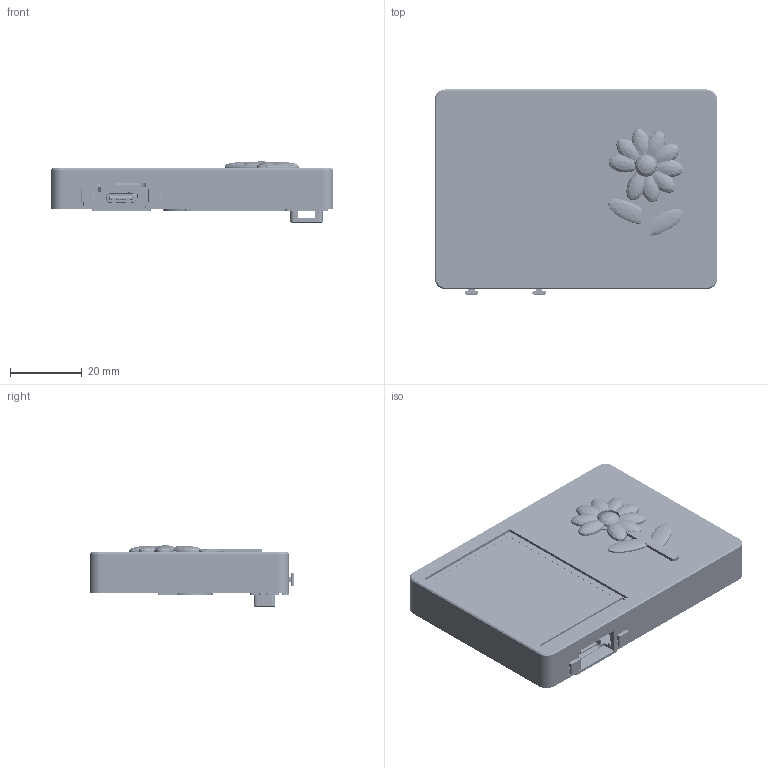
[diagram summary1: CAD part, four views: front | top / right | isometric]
STEP (ISO 10303-21) file: header records copied from the file, then geometry measured from it (millimetres).
FILE_DESCRIPTION(('Open CASCADE Model'),'2;1');
FILE_NAME('Open CASCADE Shape Model','2026-11-25T12:45:01',('Author'),( 'Open CASCADE'),'Open CASCADE STEP processor 7.9','Open CASCADE 7.9' ,'Unknown');
FILE_SCHEMA(('AUTOMOTIVE_DESIGN { 1 0 10303 214 1 1 1 1 }'));
Length unit declared in the file: millimetre
Products named in the file (11): NianNian_V12_11p4mm; A_main_two_bay; C_rear_cover; E_battery_spacer; K_BOOT_cap; K_RST_cap; hardware; battery; D_daisy_petals; D2_daisy_center; D3_stem_leaves
Assembly tree (10 placements, depth 2):
  NianNian_V12_11p4mm
    A_main_two_bay
    C_rear_cover
    E_battery_spacer
    K_BOOT_cap
    K_RST_cap
    hardware
    battery
    D_daisy_petals
    D2_daisy_center
    D3_stem_leaves
Bounding box: 79 x 57.3 x 17.2 mm (x, y, z)
Volume: 34876.8 mm3; surface area: 47404.6 mm2
Topology: 333 solids, 345 shells, 18054 faces, 47680 edges, 30993 vertices
Faces by surface type: plane 11942, extrusion 3289, cylinder 2337, sphere 331, cone 65, bspline 46, torus 44
Full cylindrical faces by diameter (mm): 1.1 x2, 1.2 x2, 1.4 x2, 1.9 x2, 3 x5, 6.57 x2
Entity records: 1404086 total; most frequent: CARTESIAN_POINT 481151, DIRECTION 155706, VECTOR 114755, LINE 111466, ORIENTED_EDGE 94686, PCURVE 94686, DEFINITIONAL_REPRESENTATION 94686, EDGE_CURVE 47343
One B-rep face of a CAD part: STEP entity #33258.
In plain terms, the planar face has unit normal (0, 0, 1).
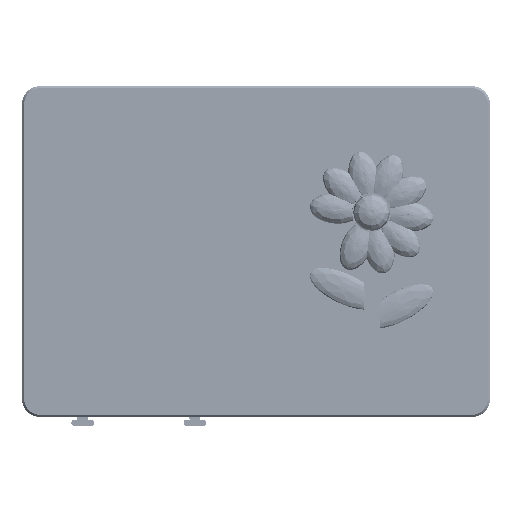
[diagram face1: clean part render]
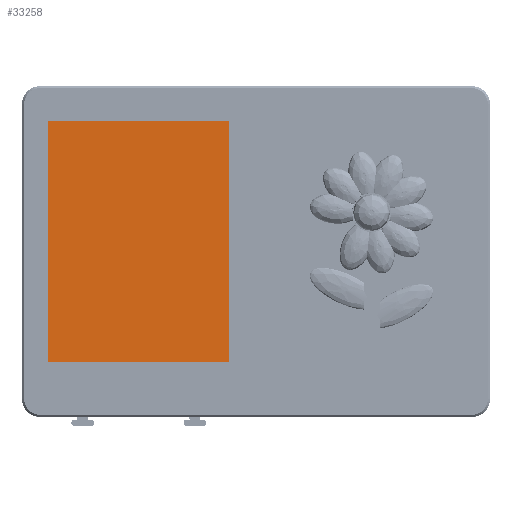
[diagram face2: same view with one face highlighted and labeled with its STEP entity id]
Its self-contained STEP definition (entity closure, numbers rounded to 3 decimals):
#33089 = PLANE('',#33090);
#33090 = AXIS2_PLACEMENT_3D('',#33091,#33092,#33093);
#33091 = CARTESIAN_POINT('',(-35.1,22.1,10.3));
#33092 = DIRECTION('',(0.,-1.,0.));
#33093 = DIRECTION('',(1.,0.,0.));
#33117 = PLANE('',#33118);
#33118 = AXIS2_PLACEMENT_3D('',#33119,#33120,#33121);
#33119 = CARTESIAN_POINT('',(-35.1,-18.7,10.3));
#33120 = DIRECTION('',(1.,0.,0.));
#33121 = DIRECTION('',(0.,1.,0.));
#33145 = PLANE('',#33146);
#33146 = AXIS2_PLACEMENT_3D('',#33147,#33148,#33149);
#33147 = CARTESIAN_POINT('',(-4.5,-18.7,10.3));
#33148 = DIRECTION('',(0.,1.,0.));
#33149 = DIRECTION('',(-1.,0.,0.));
#33171 = PLANE('',#33172);
#33172 = AXIS2_PLACEMENT_3D('',#33173,#33174,#33175);
#33173 = CARTESIAN_POINT('',(-4.5,22.1,10.3));
#33174 = DIRECTION('',(-1.,0.,0.));
#33175 = DIRECTION('',(0.,-1.,0.));
#33186 = EDGE_CURVE('',#33187,#33189,#33191,.T.);
#33187 = VERTEX_POINT('',#33188);
#33188 = CARTESIAN_POINT('',(-35.1,22.1,10.35));
#33189 = VERTEX_POINT('',#33190);
#33190 = CARTESIAN_POINT('',(-4.5,22.1,10.35));
#33191 = SURFACE_CURVE('',#33192,(#33196,#33203),.PCURVE_S1.);
#33192 = LINE('',#33193,#33194);
#33193 = CARTESIAN_POINT('',(-35.1,22.1,10.35));
#33194 = VECTOR('',#33195,1.);
#33195 = DIRECTION('',(1.,0.,0.));
#33196 = PCURVE('',#33089,#33197);
#33197 = DEFINITIONAL_REPRESENTATION('',(#33198),#33202);
#33198 = LINE('',#33199,#33200);
#33199 = CARTESIAN_POINT('',(0.,0.05));
#33200 = VECTOR('',#33201,1.);
#33201 = DIRECTION('',(1.,0.));
#33202 = ( GEOMETRIC_REPRESENTATION_CONTEXT(2) 
PARAMETRIC_REPRESENTATION_CONTEXT() REPRESENTATION_CONTEXT('2D SPACE',''
  ) );
#33203 = PCURVE('',#33204,#33209);
#33204 = PLANE('',#33205);
#33205 = AXIS2_PLACEMENT_3D('',#33206,#33207,#33208);
#33206 = CARTESIAN_POINT('',(-19.8,1.7,10.35));
#33207 = DIRECTION('',(0.,0.,1.));
#33208 = DIRECTION('',(1.,0.,0.));
#33209 = DEFINITIONAL_REPRESENTATION('',(#33210),#33214);
#33210 = LINE('',#33211,#33212);
#33211 = CARTESIAN_POINT('',(-15.3,20.4));
#33212 = VECTOR('',#33213,1.);
#33213 = DIRECTION('',(1.,0.));
#33214 = ( GEOMETRIC_REPRESENTATION_CONTEXT(2) 
PARAMETRIC_REPRESENTATION_CONTEXT() REPRESENTATION_CONTEXT('2D SPACE',''
  ) );
#33258 = ADVANCED_FACE('',(#33259),#33204,.T.);
#33259 = FACE_BOUND('',#33260,.F.);
#33260 = EDGE_LOOP('',(#33261,#33262,#33285,#33308));
#33261 = ORIENTED_EDGE('',*,*,#33186,.T.);
#33262 = ORIENTED_EDGE('',*,*,#33263,.F.);
#33263 = EDGE_CURVE('',#33264,#33189,#33266,.T.);
#33264 = VERTEX_POINT('',#33265);
#33265 = CARTESIAN_POINT('',(-4.5,-18.7,10.35));
#33266 = SURFACE_CURVE('',#33267,(#33271,#33278),.PCURVE_S1.);
#33267 = LINE('',#33268,#33269);
#33268 = CARTESIAN_POINT('',(-4.5,-18.7,10.35));
#33269 = VECTOR('',#33270,1.);
#33270 = DIRECTION('',(0.,1.,0.));
#33271 = PCURVE('',#33204,#33272);
#33272 = DEFINITIONAL_REPRESENTATION('',(#33273),#33277);
#33273 = LINE('',#33274,#33275);
#33274 = CARTESIAN_POINT('',(15.3,-20.4));
#33275 = VECTOR('',#33276,1.);
#33276 = DIRECTION('',(0.,1.));
#33277 = ( GEOMETRIC_REPRESENTATION_CONTEXT(2) 
PARAMETRIC_REPRESENTATION_CONTEXT() REPRESENTATION_CONTEXT('2D SPACE',''
  ) );
#33278 = PCURVE('',#33171,#33279);
#33279 = DEFINITIONAL_REPRESENTATION('',(#33280),#33284);
#33280 = LINE('',#33281,#33282);
#33281 = CARTESIAN_POINT('',(40.8,0.05));
#33282 = VECTOR('',#33283,1.);
#33283 = DIRECTION('',(-1.,0.));
#33284 = ( GEOMETRIC_REPRESENTATION_CONTEXT(2) 
PARAMETRIC_REPRESENTATION_CONTEXT() REPRESENTATION_CONTEXT('2D SPACE',''
  ) );
#33285 = ORIENTED_EDGE('',*,*,#33286,.F.);
#33286 = EDGE_CURVE('',#33287,#33264,#33289,.T.);
#33287 = VERTEX_POINT('',#33288);
#33288 = CARTESIAN_POINT('',(-35.1,-18.7,10.35));
#33289 = SURFACE_CURVE('',#33290,(#33294,#33301),.PCURVE_S1.);
#33290 = LINE('',#33291,#33292);
#33291 = CARTESIAN_POINT('',(-35.1,-18.7,10.35));
#33292 = VECTOR('',#33293,1.);
#33293 = DIRECTION('',(1.,0.,0.));
#33294 = PCURVE('',#33204,#33295);
#33295 = DEFINITIONAL_REPRESENTATION('',(#33296),#33300);
#33296 = LINE('',#33297,#33298);
#33297 = CARTESIAN_POINT('',(-15.3,-20.4));
#33298 = VECTOR('',#33299,1.);
#33299 = DIRECTION('',(1.,0.));
#33300 = ( GEOMETRIC_REPRESENTATION_CONTEXT(2) 
PARAMETRIC_REPRESENTATION_CONTEXT() REPRESENTATION_CONTEXT('2D SPACE',''
  ) );
#33301 = PCURVE('',#33145,#33302);
#33302 = DEFINITIONAL_REPRESENTATION('',(#33303),#33307);
#33303 = LINE('',#33304,#33305);
#33304 = CARTESIAN_POINT('',(30.6,0.05));
#33305 = VECTOR('',#33306,1.);
#33306 = DIRECTION('',(-1.,0.));
#33307 = ( GEOMETRIC_REPRESENTATION_CONTEXT(2) 
PARAMETRIC_REPRESENTATION_CONTEXT() REPRESENTATION_CONTEXT('2D SPACE',''
  ) );
#33308 = ORIENTED_EDGE('',*,*,#33309,.T.);
#33309 = EDGE_CURVE('',#33287,#33187,#33310,.T.);
#33310 = SURFACE_CURVE('',#33311,(#33315,#33322),.PCURVE_S1.);
#33311 = LINE('',#33312,#33313);
#33312 = CARTESIAN_POINT('',(-35.1,-18.7,10.35));
#33313 = VECTOR('',#33314,1.);
#33314 = DIRECTION('',(0.,1.,0.));
#33315 = PCURVE('',#33204,#33316);
#33316 = DEFINITIONAL_REPRESENTATION('',(#33317),#33321);
#33317 = LINE('',#33318,#33319);
#33318 = CARTESIAN_POINT('',(-15.3,-20.4));
#33319 = VECTOR('',#33320,1.);
#33320 = DIRECTION('',(0.,1.));
#33321 = ( GEOMETRIC_REPRESENTATION_CONTEXT(2) 
PARAMETRIC_REPRESENTATION_CONTEXT() REPRESENTATION_CONTEXT('2D SPACE',''
  ) );
#33322 = PCURVE('',#33117,#33323);
#33323 = DEFINITIONAL_REPRESENTATION('',(#33324),#33328);
#33324 = LINE('',#33325,#33326);
#33325 = CARTESIAN_POINT('',(0.,0.05));
#33326 = VECTOR('',#33327,1.);
#33327 = DIRECTION('',(1.,0.));
#33328 = ( GEOMETRIC_REPRESENTATION_CONTEXT(2) 
PARAMETRIC_REPRESENTATION_CONTEXT() REPRESENTATION_CONTEXT('2D SPACE',''
  ) );
